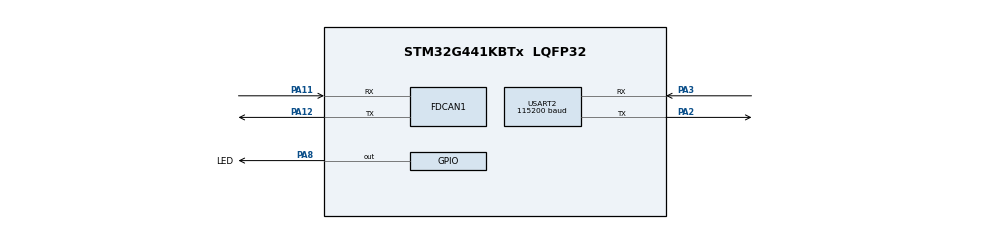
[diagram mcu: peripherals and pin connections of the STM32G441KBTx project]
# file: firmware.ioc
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Dma.Request0=USART2_RX
Dma.Request1=USART2_TX
Dma.USART2_RX.0.Direction=DMA_PERIPH_TO_MEMORY
Dma.USART2_RX.0.EventEnable=DISABLE
Dma.USART2_RX.0.Instance=DMA1_Channel1
Dma.USART2_RX.0.MemDataAlignment=DMA_MDATAALIGN_BYTE
Dma.USART2_RX.0.MemInc=DMA_MINC_ENABLE
Dma.USART2_RX.0.Mode=DMA_CIRCULAR
Dma.USART2_RX.0.PeriphDataAlignment=DMA_PDATAALIGN_BYTE
Dma.USART2_RX.0.PeriphInc=DMA_PINC_DISABLE
Dma.USART2_RX.0.Polarity=HAL_DMAMUX_REQ_GEN_RISING
Dma.USART2_RX.0.Priority=DMA_PRIORITY_HIGH
Dma.USART2_RX.0.RequestNumber=1
Dma.USART2_RX.0.SignalID=NONE
Dma.USART2_RX.0.SyncEnable=DISABLE
Dma.USART2_RX.0.SyncPolarity=HAL_DMAMUX_SYNC_NO_EVENT
Dma.USART2_RX.0.SyncRequestNumber=1
Dma.USART2_RX.0.SyncSignalID=NONE
Dma.USART2_TX.1.Direction=DMA_MEMORY_TO_PERIPH
Dma.USART2_TX.1.EventEnable=DISABLE
Dma.USART2_TX.1.Instance=DMA1_Channel2
Dma.USART2_TX.1.MemDataAlignment=DMA_MDATAALIGN_BYTE
Dma.USART2_TX.1.MemInc=DMA_MINC_ENABLE
Dma.USART2_TX.1.Mode=DMA_NORMAL
Dma.USART2_TX.1.PeriphDataAlignment=DMA_PDATAALIGN_BYTE
Dma.USART2_TX.1.PeriphInc=DMA_PINC_DISABLE
Dma.USART2_TX.1.Polarity=HAL_DMAMUX_REQ_GEN_RISING
Dma.USART2_TX.1.Priority=DMA_PRIORITY_LOW
Dma.USART2_TX.1.RequestNumber=1
Dma.USART2_TX.1.SignalID=NONE
Dma.USART2_TX.1.SyncEnable=DISABLE
Dma.USART2_TX.1.SyncPolarity=HAL_DMAMUX_SYNC_NO_EVENT
Dma.USART2_TX.1.SyncRequestNumber=1
Dma.USART2_TX.1.SyncSignalID=NONE
FDCAN1.CalculateBaudRateNominal=500000
FDCAN1.CalculateTimeBitNominal=2000
FDCAN1.CalculateTimeQuantumNominal=125.0
FDCAN1.DataPrescaler=2
FDCAN1.DataSyncJumpWidth=4
FDCAN1.DataTimeSeg1=8
FDCAN1.DataTimeSeg2=3
FDCAN1.FrameFormat=FDCAN_FRAME_FD_BRS
FDCAN1.NominalPrescaler=6
FDCAN1.NominalSyncJumpWidth=4
FDCAN1.NominalTimeSeg1=9
FDCAN1.NominalTimeSeg2=6
FDCAN1.ProtocolException=ENABLE
FDCAN1.StdFiltersNbr=1
FREERTOS.Tasks01=defaultTask,24,128,StartDefaultTask,Default,NULL,Dynamic,NULL,NULL
FREERTOS.configTOTAL_HEAP_SIZE=8192
FREERTOS.configUSE_NEWLIB_REENTRANT=1
Mcu.Family=STM32G4
Mcu.Name=STM32G441KBTx
Mcu.Package=LQFP32
NVIC.DMA1_Channel1_IRQn=true\:5\:0\:false\:false\:true\:true\:false\:true\:true
NVIC.DMA1_Channel2_IRQn=true\:5\:0\:false\:false\:true\:true\:false\:true\:true
NVIC.FDCAN1_IT0_IRQn=true\:5\:0\:false\:false\:true\:true\:true\:true\:true
NVIC.PriorityGroup=NVIC_PRIORITYGROUP_4
NVIC.TIM1_TRG_COM_TIM17_IRQn=true\:15\:0\:false\:false\:true\:false\:false\:true\:true
NVIC.TimeBase=TIM1_TRG_COM_TIM17_IRQn
NVIC.TimeBaseIP=TIM17
NVIC.USART2_IRQn=true\:5\:0\:false\:false\:true\:true\:true\:true\:true
PA11.Mode=FDCAN_Activate
PA11.Signal=FDCAN1_RX
PA12.Mode=FDCAN_Activate
PA12.Signal=FDCAN1_TX
PA13.Mode=Serial_Wire
PA13.Signal=SYS_JTMS-SWDIO
PA14.Mode=Serial_Wire
PA14.Signal=SYS_JTCK-SWCLK
PA2.Mode=Asynchronous
PA2.Signal=USART2_TX
PA3.Mode=Asynchronous
PA3.Signal=USART2_RX
PA8.GPIO_Label=LED
PA8.Signal=GPIO_Output
ProjectManager.HeapSize=0x200
ProjectManager.StackSize=0x400
ProjectManager.TargetToolchain=CMake
RCC.ADC12Freq_Value=144000000
RCC.AHBFreq_Value=144000000
RCC.APB1Freq_Value=144000000
RCC.APB1TimFreq_Value=144000000
RCC.APB2Freq_Value=144000000
RCC.APB2TimFreq_Value=144000000
RCC.CortexFreq_Value=144000000
RCC.EXTERNAL_CLOCK_VALUE=12288000
RCC.FDCANCLockSelection=RCC_FDCANCLKSOURCE_PLL
RCC.HCLKFreq_Value=144000000
RCC.HSE_VALUE=8000000
RCC.HSI48_VALUE=48000000
RCC.HSI_VALUE=16000000
RCC.LSE_VALUE=32768
RCC.PLLN=18
RCC.PLLQ=RCC_PLLQ_DIV6
RCC.SYSCLKFreq_VALUE=144000000
RCC.SYSCLKSource=RCC_SYSCLKSOURCE_PLLCLK
RCC.USBFreq_Value=48000000
RCC.VCOOutputFreq_Value=288000000
USART2.BaudRate=115200
USART2.VirtualMode-Asynchronous=VM_ASYNC
VP_FREERTOS_VS_CMSIS_V2.Mode=CMSIS_V2
VP_SYS_VS_DBSignals.Mode=DisableDeadBatterySignals
VP_SYS_VS_tim17.Mode=TIM17
board=custom

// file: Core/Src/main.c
/* USER CODE BEGIN Header */
/**
  ******************************************************************************
  * @file           : main.c
  * @brief          : Main program body
  ******************************************************************************
  * @attention
  *
  * Copyright (c) 2025 STMicroelectronics.
  * All rights reserved.
  *
  * This software is licensed under terms that can be found in the LICENSE file
  * in the root directory of this software component.
  * If no LICENSE file comes with this software, it is provided AS-IS.
  *
  ******************************************************************************
  */
/* USER CODE END Header */
#include "main.h"
#include "cmsis_os.h"
#include "fdcan.h"
#include "usart.h"
#include "gpio.h"

/* USER CODE BEGIN Includes */
#include "SEGGER_RTT.h"
/* USER CODE END Includes */

void SystemClock_Config(void);
void MX_FREERTOS_Init(void);

int main(void)
{

  /* USER CODE BEGIN 1 */
	SEGGER_RTT_Init();
  /* USER CODE END 1 */

  /* MCU Configuration--------------------------------------------------------*/

  /* Reset of all peripherals, Initializes the Flash interface and the Systick. */
  HAL_Init();

  /* USER CODE BEGIN Init */
	SEGGER_RTT_printf(0,"program started\n");
  /* USER CODE END Init */

  /* Configure the system clock */
  SystemClock_Config();

  /* Initialize all configured peripherals */
  MX_GPIO_Init();
  MX_FDCAN1_Init();
  MX_USART2_UART_Init();
  /* USER CODE BEGIN 2 */

	if (HAL_FDCAN_Start(&hfdcan1) != HAL_OK)
	{
		Error_Handler();
	}

	// Activate the notification for new data in FIFO0 for FDCAN1
	if (HAL_FDCAN_ActivateNotification(&hfdcan1, FDCAN_IT_RX_FIFO0_NEW_MESSAGE, 0) != HAL_OK)
	{
		Error_Handler();
	}

  /* USER CODE END 2 */

  /* Init scheduler */
  osKernelInitialize();

  /* Call init function for freertos objects (in cmsis_os2.c) */
  MX_FREERTOS_Init();

  /* Start scheduler */
  osKernelStart();

  /* We should never get here as control is now taken by the scheduler */

  /* Infinite loop */
  while (1)
  {

  }
}

void SystemClock_Config(void)
{
  RCC_OscInitTypeDef RCC_OscInitStruct = {0};
  RCC_ClkInitTypeDef RCC_ClkInitStruct = {0};

  /** Configure the main internal regulator output voltage
  */
  HAL_PWREx_ControlVoltageScaling(PWR_REGULATOR_VOLTAGE_SCALE1);

  /** Initializes the RCC Oscillators according to the specified parameters
  * in the RCC_OscInitTypeDef structure.
  */
  RCC_OscInitStruct.OscillatorType = RCC_OSCILLATORTYPE_HSI;
  RCC_OscInitStruct.HSIState = RCC_HSI_ON;
  RCC_OscInitStruct.HSICalibrationValue = RCC_HSICALIBRATION_DEFAULT;
  RCC_OscInitStruct.PLL.PLLState = RCC_PLL_ON;
  RCC_OscInitStruct.PLL.PLLSource = RCC_PLLSOURCE_HSI;
  RCC_OscInitStruct.PLL.PLLM = RCC_PLLM_DIV1;
  RCC_OscInitStruct.PLL.PLLN = 8;
  RCC_OscInitStruct.PLL.PLLP = RCC_PLLP_DIV2;
  RCC_OscInitStruct.PLL.PLLQ = RCC_PLLQ_DIV4;
  RCC_OscInitStruct.PLL.PLLR = RCC_PLLR_DIV2;
  if (HAL_RCC_OscConfig(&RCC_OscInitStruct) != HAL_OK)
  {
    Error_Handler();
  }

  /** Initializes the CPU, AHB and APB buses clocks
  */
  RCC_ClkInitStruct.ClockType = RCC_CLOCKTYPE_HCLK|RCC_CLOCKTYPE_SYSCLK
                              |RCC_CLOCKTYPE_PCLK1|RCC_CLOCKTYPE_PCLK2;
  RCC_ClkInitStruct.SYSCLKSource = RCC_SYSCLKSOURCE_PLLCLK;
  RCC_ClkInitStruct.AHBCLKDivider = RCC_SYSCLK_DIV1;
  RCC_ClkInitStruct.APB1CLKDivider = RCC_HCLK_DIV1;
  RCC_ClkInitStruct.APB2CLKDivider = RCC_HCLK_DIV1;

  if (HAL_RCC_ClockConfig(&RCC_ClkInitStruct, FLASH_LATENCY_2) != HAL_OK)
  {
    Error_Handler();
  }
}

void HAL_TIM_PeriodElapsedCallback(TIM_HandleTypeDef *htim)
{
  if (htim->Instance == TIM17)
  {
    HAL_IncTick();
  }
}

void Error_Handler(void)
{
  __disable_irq();
  while (1)
  {
  }
}

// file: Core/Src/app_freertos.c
/* USER CODE BEGIN Header */
/**
 ******************************************************************************
 * File Name          : app_freertos.c
 * Description        : Code for freertos applications
 ******************************************************************************
 * @attention
 *
 * Copyright (c) 2025 STMicroelectronics.
 * All rights reserved.
 *
 * This software is licensed under terms that can be found in the LICENSE file
 * in the root directory of this software component.
 * If no LICENSE file comes with this software, it is provided AS-IS.
 *
 ******************************************************************************
 */
/* USER CODE END Header */

#include "FreeRTOS.h"
#include "task.h"
#include "main.h"
#include "cmsis_os.h"
#include "queue.h"

/* USER CODE BEGIN Includes */
#include "fdcan.h"
#include "usart.h"
#include "SEGGER_RTT.h"
#include "SensorPacket.h"
/* USER CODE END Includes */

/* USER CODE BEGIN Variables */

QueueHandle_t xQueueCANPacketHandle;

/* USER CODE END Variables */
/* Definitions for defaultTask */
osThreadId_t defaultTaskHandle;
const osThreadAttr_t defaultTask_attributes = {
    .name = "defaultTask",
    .priority = (osPriority_t)osPriorityNormal,
    .stack_size = 128 * 4};

/* USER CODE BEGIN FunctionPrototypes */
/// @brief Send packet via UART with COBS encoding
/// @param data Pointer to the data to send
/// @param size Size of the data to send
void send_pkt(uint8_t *data, uint32_t size);
/* USER CODE END FunctionPrototypes */

void StartDefaultTask(void *argument);

void MX_FREERTOS_Init(void); /* (MISRA C 2004 rule 8.1) */

void MX_FREERTOS_Init(void)
{

  /* USER CODE BEGIN RTOS_QUEUES */

  xQueueCANPacketHandle = xQueueCreate(10, sizeof(struct CANPacket));
  if (xQueueCANPacketHandle == NULL)
  {
    Error_Handler();
  }
  /* USER CODE END RTOS_QUEUES */

  /* Create the thread(s) */
  /* creation of defaultTask */
  defaultTaskHandle = osThreadNew(StartDefaultTask, NULL, &defaultTask_attributes);

}

void StartDefaultTask(void *argument)
{
  /* USER CODE BEGIN StartDefaultTask */
  /* Infinite loop */
  for (;;)
  {
    union
    {
      struct CANPacket data;
      uint8_t raw[sizeof(struct CANPacket)];
    } u;

    while (uxQueueMessagesWaiting(xQueueCANPacketHandle) > 0)
    {
      HAL_GPIO_WritePin(LED_GPIO_Port, LED_Pin, GPIO_PIN_SET);
      if (xQueueReceive(xQueueCANPacketHandle, &u.data, portMAX_DELAY) == pdTRUE)
      {
        SEGGER_RTT_printf(0, "Received CAN message: id=0x%X data=[ ", u.data.id);
        for (int32_t i = 0; i < u.data.size; i++)
        {
          SEGGER_RTT_printf(0, "0x%02X ", u.data.payload[i]);
        }
        SEGGER_RTT_printf(0, "]\n");
        send_pkt(u.raw, sizeof(u.raw));
      }
      HAL_GPIO_WritePin(LED_GPIO_Port, LED_Pin, GPIO_PIN_RESET);
    }
  }
  /* USER CODE END StartDefaultTask */
}

/* USER CODE BEGIN Application */

void HAL_FDCAN_RxFifo0Callback(FDCAN_HandleTypeDef *hfdcan, uint32_t RxFifo0ITs)
{
  FDCAN_RxHeaderTypeDef fdcan1RxHeader;
  uint8_t fdcan1RxData[64];
  struct CANPacket canPacket;

  if ((RxFifo0ITs & FDCAN_IT_RX_FIFO0_NEW_MESSAGE) != RESET)
  {

    if (HAL_FDCAN_GetRxMessage(hfdcan, FDCAN_RX_FIFO0, &fdcan1RxHeader, fdcan1RxData) != HAL_OK)
    {
      /* Reception Error */
      Error_Handler();
    }
    canPacket.id = fdcan1RxHeader.Identifier;
    canPacket.size = fdcan1RxHeader.DataLength;
    if (canPacket.size > 8)
    {
      canPacket.size = 8; // Limit size to 64 bytes
    }
    for (int32_t i = 0; i < canPacket.size; i++)
    {
      canPacket.payload[i] = fdcan1RxData[i];
    }

    xQueueSendFromISR(xQueueCANPacketHandle, &canPacket, NULL);

    if (HAL_FDCAN_ActivateNotification(&hfdcan1, FDCAN_IT_RX_FIFO0_NEW_MESSAGE, 0) != HAL_OK)
    {
      Error_Handler();
    }
  }
}

void send_pkt(uint8_t *data, uint32_t size)
{
  // COBS encoding and sending logic here
  // For now, just print the data to RTT

  uint8_t cobs_buf_idx = 0, encoded_idx = 0;
  uint8_t cobs_buf[256], encoded_data[256];

  // COBS encoding
  for (uint32_t i = 0; i < size; i++)
  {
    if (data[i] == 0)
    {
      encoded_data[encoded_idx] = cobs_buf_idx + 1;
      encoded_idx++;
      for (uint8_t j = 0; j < cobs_buf_idx; j++)
      {
        encoded_data[encoded_idx] = cobs_buf[j];
        encoded_idx++;
      }
      cobs_buf_idx = 0; // Reset for next segment
    }
    else
    {
      cobs_buf[cobs_buf_idx] = data[i];
      cobs_buf_idx++;
    }
  }
  encoded_data[encoded_idx++] = cobs_buf_idx + 1; // Final segment length
  for (uint8_t j = 0; j < cobs_buf_idx; j++)
  {
    encoded_data[encoded_idx++] = cobs_buf[j];
  }
  encoded_data[encoded_idx++] = 0; // End of COBS encoding
  // Send the COBS-encoded packet over UART
  HAL_UART_Transmit(&huart2, encoded_data, encoded_idx, HAL_MAX_DELAY);
}

/* USER CODE END Application */
